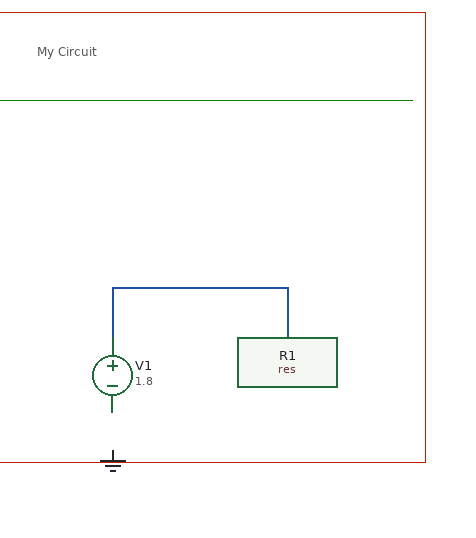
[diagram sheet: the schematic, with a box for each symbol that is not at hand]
v {xschem version=3.4.5 file_version=1.2}
G {}
K {}
V {}
S {}
E {}
C {devices/res.sym} 300 -200 0 0 {name=R1 value=10k m=1}
C {devices/vsource.sym} 160 -130 0 0 {name=V1 value=1.8}
C {devices/gnd.sym} 160 -70 0 0 {name=l1 lab=GND}
N 160 -160 160 -200 {lab=VDD}
N 300 -160 300 -200 {}
N 160 -200 300 -200 {lab=net1}
T {My Circuit} 100 -400 0 0 0.3 0.3 {}
L 4 50 -350 400 -350 {}
B 5 40 -420 410 -60 {dash=4}
A 4 200 -150 50 0 360 {}
P 4 3 500 -100 600 -100 550 -200 {}
